VERSION 5.7 ;
  NOWIREEXTENSIONATPIN ON ;
  DIVIDERCHAR "/" ;
  BUSBITCHARS "[]" ;
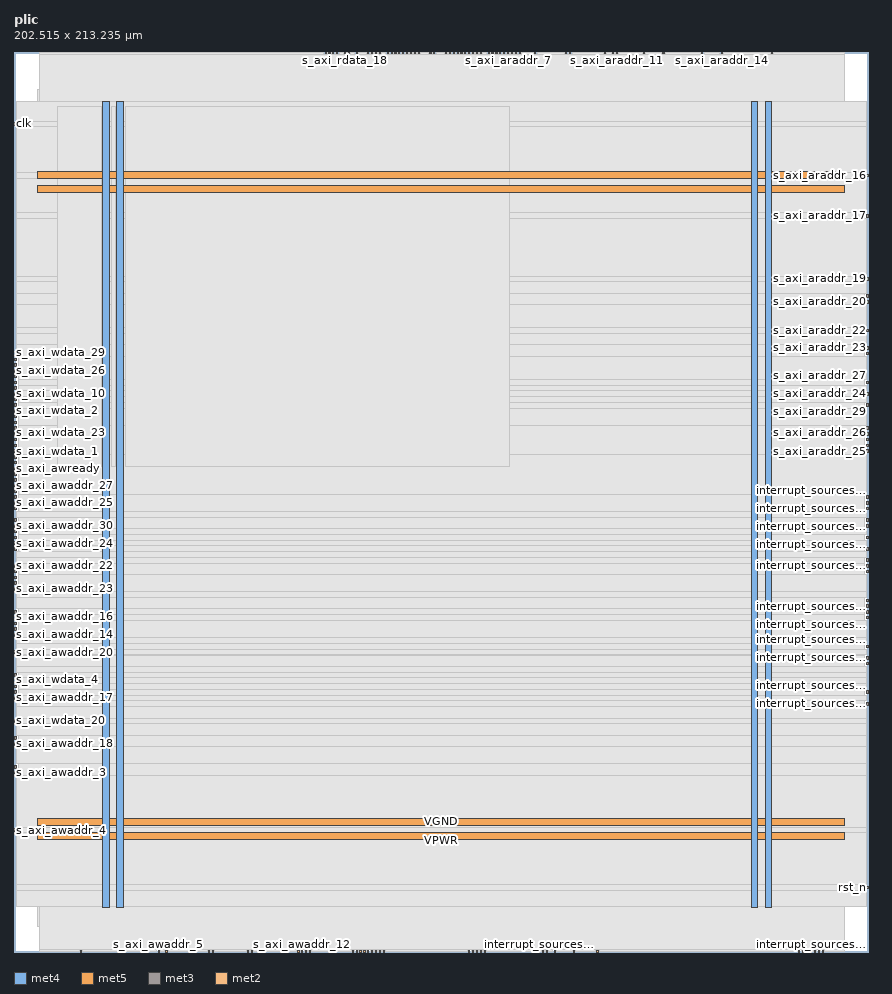
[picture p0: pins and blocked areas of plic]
MACRO plic
  CLASS BLOCK ;
  FOREIGN plic ;
  ORIGIN 0.000 0.000 ;
  SIZE 202.515 BY 213.235 ;
  PIN VGND
    DIRECTION INOUT ;
    USE GROUND ;
    PORT
      LAYER met4 ;
        RECT 24.340 10.640 25.940 201.520 ;
    END
    PORT
      LAYER met4 ;
        RECT 177.940 10.640 179.540 201.520 ;
    END
    PORT
      LAYER met5 ;
        RECT 5.520 30.030 196.880 31.630 ;
    END
    PORT
      LAYER met5 ;
        RECT 5.520 183.210 196.880 184.810 ;
    END
  END VGND
  PIN VPWR
    DIRECTION INOUT ;
    USE POWER ;
    PORT
      LAYER met4 ;
        RECT 21.040 10.640 22.640 201.520 ;
    END
    PORT
      LAYER met4 ;
        RECT 174.640 10.640 176.240 201.520 ;
    END
    PORT
      LAYER met5 ;
        RECT 5.520 26.730 196.880 28.330 ;
    END
    PORT
      LAYER met5 ;
        RECT 5.520 179.910 196.880 181.510 ;
    END
  END VPWR
  PIN clk
    DIRECTION INPUT ;
    USE SIGNAL ;
    ANTENNAGATEAREA 1.286700 ;
    ANTENNADIFFAREA 0.434700 ;
    PORT
      LAYER met3 ;
        RECT 0.000 195.880 0.600 196.480 ;
    END
  END clk
  PIN ext_irq
    DIRECTION OUTPUT ;
    USE SIGNAL ;
    ANTENNAGATEAREA 0.434700 ;
    ANTENNADIFFAREA 0.434700 ;
    PORT
      LAYER met2 ;
        RECT 111.410 0.000 111.690 0.280 ;
    END
  END ext_irq
  PIN interrupt_sources_0
    DIRECTION INPUT ;
    USE SIGNAL ;
    ANTENNAGATEAREA 0.647700 ;
    ANTENNADIFFAREA 0.434700 ;
    PORT
      LAYER met2 ;
        RECT 191.450 0.000 191.730 0.280 ;
    END
  END interrupt_sources_0
  PIN interrupt_sources_1
    DIRECTION INPUT ;
    USE SIGNAL ;
    ANTENNAGATEAREA 0.647700 ;
    ANTENNADIFFAREA 0.434700 ;
    PORT
      LAYER met3 ;
        RECT 201.915 104.760 202.515 105.360 ;
    END
  END interrupt_sources_1
  PIN interrupt_sources_10
    DIRECTION INPUT ;
    USE SIGNAL ;
    ANTENNAGATEAREA 0.647700 ;
    ANTENNADIFFAREA 0.434700 ;
    PORT
      LAYER met3 ;
        RECT 201.915 61.240 202.515 61.840 ;
    END
  END interrupt_sources_10
  PIN interrupt_sources_11
    DIRECTION INPUT ;
    USE SIGNAL ;
    ANTENNAGATEAREA 0.647700 ;
    ANTENNADIFFAREA 0.434700 ;
    PORT
      LAYER met3 ;
        RECT 201.915 69.400 202.515 70.000 ;
    END
  END interrupt_sources_11
  PIN interrupt_sources_12
    DIRECTION INPUT ;
    USE SIGNAL ;
    ANTENNAGATEAREA 0.647700 ;
    ANTENNADIFFAREA 0.434700 ;
    PORT
      LAYER met3 ;
        RECT 201.915 102.040 202.515 102.640 ;
    END
  END interrupt_sources_12
  PIN interrupt_sources_13
    DIRECTION INPUT ;
    USE SIGNAL ;
    ANTENNAGATEAREA 0.647700 ;
    ANTENNADIFFAREA 0.434700 ;
    PORT
      LAYER met3 ;
        RECT 201.915 58.520 202.515 59.120 ;
    END
  END interrupt_sources_13
  PIN interrupt_sources_14
    DIRECTION INPUT ;
    USE SIGNAL ;
    ANTENNAGATEAREA 0.647700 ;
    ANTENNADIFFAREA 0.434700 ;
    PORT
      LAYER met2 ;
        RECT 125.210 0.000 125.490 0.280 ;
    END
  END interrupt_sources_14
  PIN interrupt_sources_15
    DIRECTION INPUT ;
    USE SIGNAL ;
    ANTENNAGATEAREA 0.647700 ;
    ANTENNADIFFAREA 0.434700 ;
    PORT
      LAYER met3 ;
        RECT 201.915 81.640 202.515 82.240 ;
    END
  END interrupt_sources_15
  PIN interrupt_sources_16
    DIRECTION INPUT ;
    USE SIGNAL ;
    ANTENNAGATEAREA 0.647700 ;
    ANTENNADIFFAREA 0.434700 ;
    PORT
      LAYER met2 ;
        RECT 189.610 0.000 189.890 0.280 ;
    END
  END interrupt_sources_16
  PIN interrupt_sources_17
    DIRECTION INPUT ;
    USE SIGNAL ;
    ANTENNAGATEAREA 0.647700 ;
    ANTENNADIFFAREA 0.434700 ;
    PORT
      LAYER met3 ;
        RECT 201.915 107.480 202.515 108.080 ;
    END
  END interrupt_sources_17
  PIN interrupt_sources_18
    DIRECTION INPUT ;
    USE SIGNAL ;
    ANTENNAGATEAREA 0.647700 ;
    ANTENNADIFFAREA 0.434700 ;
    PORT
      LAYER met3 ;
        RECT 201.915 72.120 202.515 72.720 ;
    END
  END interrupt_sources_18
  PIN interrupt_sources_19
    DIRECTION INPUT ;
    USE SIGNAL ;
    ANTENNAGATEAREA 0.647700 ;
    ANTENNADIFFAREA 0.434700 ;
    PORT
      LAYER met2 ;
        RECT 187.770 0.000 188.050 0.280 ;
    END
  END interrupt_sources_19
  PIN interrupt_sources_2
    DIRECTION INPUT ;
    USE SIGNAL ;
    ANTENNAGATEAREA 0.647700 ;
    ANTENNADIFFAREA 0.434700 ;
    PORT
      LAYER met3 ;
        RECT 201.915 106.120 202.515 106.720 ;
    END
  END interrupt_sources_2
  PIN interrupt_sources_20
    DIRECTION INPUT ;
    USE SIGNAL ;
    ANTENNAGATEAREA 0.647700 ;
    ANTENNADIFFAREA 0.434700 ;
    PORT
      LAYER met2 ;
        RECT 138.090 0.000 138.370 0.280 ;
    END
  END interrupt_sources_20
  PIN interrupt_sources_21
    DIRECTION INPUT ;
    USE SIGNAL ;
    ANTENNAGATEAREA 0.647700 ;
    ANTENNADIFFAREA 0.434700 ;
    PORT
      LAYER met2 ;
        RECT 186.850 0.000 187.130 0.280 ;
    END
  END interrupt_sources_21
  PIN interrupt_sources_22
    DIRECTION INPUT ;
    USE SIGNAL ;
    ANTENNAGATEAREA 0.647700 ;
    ANTENNADIFFAREA 0.434700 ;
    PORT
      LAYER met2 ;
        RECT 127.970 0.000 128.250 0.280 ;
    END
  END interrupt_sources_22
  PIN interrupt_sources_23
    DIRECTION INPUT ;
    USE SIGNAL ;
    ANTENNAGATEAREA 0.647700 ;
    ANTENNADIFFAREA 0.434700 ;
    PORT
      LAYER met2 ;
        RECT 126.130 0.000 126.410 0.280 ;
    END
  END interrupt_sources_23
  PIN interrupt_sources_24
    DIRECTION INPUT ;
    USE SIGNAL ;
    ANTENNAGATEAREA 0.647700 ;
    ANTENNADIFFAREA 0.434700 ;
    PORT
      LAYER met3 ;
        RECT 201.915 83.000 202.515 83.600 ;
    END
  END interrupt_sources_24
  PIN interrupt_sources_25
    DIRECTION INPUT ;
    USE SIGNAL ;
    ANTENNAGATEAREA 0.647700 ;
    ANTENNADIFFAREA 0.434700 ;
    PORT
      LAYER met3 ;
        RECT 201.915 68.040 202.515 68.640 ;
    END
  END interrupt_sources_25
  PIN interrupt_sources_26
    DIRECTION INPUT ;
    USE SIGNAL ;
    ANTENNAGATEAREA 0.647700 ;
    ANTENNADIFFAREA 0.434700 ;
    PORT
      LAYER met3 ;
        RECT 201.915 91.160 202.515 91.760 ;
    END
  END interrupt_sources_26
  PIN interrupt_sources_27
    DIRECTION INPUT ;
    USE SIGNAL ;
    ANTENNAGATEAREA 0.647700 ;
    ANTENNADIFFAREA 0.434700 ;
    PORT
      LAYER met2 ;
        RECT 190.530 0.000 190.810 0.280 ;
    END
  END interrupt_sources_27
  PIN interrupt_sources_28
    DIRECTION INPUT ;
    USE SIGNAL ;
    ANTENNAGATEAREA 0.647700 ;
    ANTENNADIFFAREA 0.434700 ;
    PORT
      LAYER met3 ;
        RECT 201.915 97.960 202.515 98.560 ;
    END
  END interrupt_sources_28
  PIN interrupt_sources_29
    DIRECTION INPUT ;
    USE SIGNAL ;
    ANTENNAGATEAREA 0.647700 ;
    ANTENNADIFFAREA 0.434700 ;
    PORT
      LAYER met3 ;
        RECT 201.915 89.800 202.515 90.400 ;
    END
  END interrupt_sources_29
  PIN interrupt_sources_3
    DIRECTION INPUT ;
    USE SIGNAL ;
    ANTENNAGATEAREA 0.647700 ;
    ANTENNADIFFAREA 0.434700 ;
    PORT
      LAYER met2 ;
        RECT 185.930 0.000 186.210 0.280 ;
    END
  END interrupt_sources_3
  PIN interrupt_sources_30
    DIRECTION INPUT ;
    USE SIGNAL ;
    ANTENNAGATEAREA 0.647700 ;
    ANTENNADIFFAREA 0.434700 ;
    PORT
      LAYER met3 ;
        RECT 201.915 95.240 202.515 95.840 ;
    END
  END interrupt_sources_30
  PIN interrupt_sources_31
    DIRECTION INPUT ;
    USE SIGNAL ;
    ANTENNAGATEAREA 0.647700 ;
    ANTENNADIFFAREA 0.434700 ;
    PORT
      LAYER met3 ;
        RECT 201.915 92.520 202.515 93.120 ;
    END
  END interrupt_sources_31
  PIN interrupt_sources_4
    DIRECTION INPUT ;
    USE SIGNAL ;
    ANTENNAGATEAREA 0.647700 ;
    ANTENNADIFFAREA 0.434700 ;
    PORT
      LAYER met3 ;
        RECT 201.915 80.280 202.515 80.880 ;
    END
  END interrupt_sources_4
  PIN interrupt_sources_5
    DIRECTION INPUT ;
    USE SIGNAL ;
    ANTENNAGATEAREA 0.647700 ;
    ANTENNADIFFAREA 0.434700 ;
    PORT
      LAYER met2 ;
        RECT 188.690 0.000 188.970 0.280 ;
    END
  END interrupt_sources_5
  PIN interrupt_sources_6
    DIRECTION INPUT ;
    USE SIGNAL ;
    ANTENNAGATEAREA 0.647700 ;
    ANTENNADIFFAREA 0.434700 ;
    PORT
      LAYER met2 ;
        RECT 124.290 0.000 124.570 0.280 ;
    END
  END interrupt_sources_6
  PIN interrupt_sources_7
    DIRECTION INPUT ;
    USE SIGNAL ;
    ANTENNAGATEAREA 0.647700 ;
    ANTENNADIFFAREA 0.434700 ;
    PORT
      LAYER met2 ;
        RECT 132.570 0.000 132.850 0.280 ;
    END
  END interrupt_sources_7
  PIN interrupt_sources_8
    DIRECTION INPUT ;
    USE SIGNAL ;
    ANTENNAGATEAREA 0.647700 ;
    ANTENNADIFFAREA 0.434700 ;
    PORT
      LAYER met3 ;
        RECT 201.915 78.920 202.515 79.520 ;
    END
  END interrupt_sources_8
  PIN interrupt_sources_9
    DIRECTION INPUT ;
    USE SIGNAL ;
    ANTENNAGATEAREA 0.647700 ;
    ANTENNADIFFAREA 0.434700 ;
    PORT
      LAYER met3 ;
        RECT 201.915 100.680 202.515 101.280 ;
    END
  END interrupt_sources_9
  PIN rst_n
    DIRECTION INPUT ;
    USE SIGNAL ;
    ANTENNAGATEAREA 0.647700 ;
    ANTENNADIFFAREA 0.434700 ;
    PORT
      LAYER met3 ;
        RECT 201.915 15.000 202.515 15.600 ;
    END
  END rst_n
  PIN s_axi_araddr_0
    DIRECTION INPUT ;
    USE SIGNAL ;
    ANTENNAGATEAREA 0.647700 ;
    ANTENNADIFFAREA 0.434700 ;
    PORT
      LAYER met2 ;
        RECT 130.730 212.955 131.010 213.235 ;
    END
  END s_axi_araddr_0
  PIN s_axi_araddr_1
    DIRECTION INPUT ;
    USE SIGNAL ;
    ANTENNAGATEAREA 0.647700 ;
    ANTENNADIFFAREA 0.434700 ;
    PORT
      LAYER met2 ;
        RECT 116.010 212.955 116.290 213.235 ;
    END
  END s_axi_araddr_1
  PIN s_axi_araddr_10
    DIRECTION INPUT ;
    USE SIGNAL ;
    ANTENNAGATEAREA 0.647700 ;
    ANTENNADIFFAREA 0.434700 ;
    PORT
      LAYER met2 ;
        RECT 131.650 212.955 131.930 213.235 ;
    END
  END s_axi_araddr_10
  PIN s_axi_araddr_11
    DIRECTION INPUT ;
    USE SIGNAL ;
    ANTENNAGATEAREA 0.647700 ;
    ANTENNADIFFAREA 0.434700 ;
    PORT
      LAYER met2 ;
        RECT 142.690 212.955 142.970 213.235 ;
    END
  END s_axi_araddr_11
  PIN s_axi_araddr_12
    DIRECTION INPUT ;
    USE SIGNAL ;
    ANTENNAGATEAREA 0.647700 ;
    ANTENNADIFFAREA 0.434700 ;
    PORT
      LAYER met2 ;
        RECT 149.130 212.955 149.410 213.235 ;
    END
  END s_axi_araddr_12
  PIN s_axi_araddr_13
    DIRECTION INPUT ;
    USE SIGNAL ;
    ANTENNAGATEAREA 0.647700 ;
    ANTENNADIFFAREA 0.434700 ;
    PORT
      LAYER met2 ;
        RECT 153.730 212.955 154.010 213.235 ;
    END
  END s_axi_araddr_13
  PIN s_axi_araddr_14
    DIRECTION INPUT ;
    USE SIGNAL ;
    ANTENNAGATEAREA 0.647700 ;
    ANTENNADIFFAREA 0.434700 ;
    PORT
      LAYER met2 ;
        RECT 167.530 212.955 167.810 213.235 ;
    END
  END s_axi_araddr_14
  PIN s_axi_araddr_15
    DIRECTION INPUT ;
    USE SIGNAL ;
    ANTENNAGATEAREA 0.647700 ;
    ANTENNADIFFAREA 0.434700 ;
    PORT
      LAYER met2 ;
        RECT 179.490 212.955 179.770 213.235 ;
    END
  END s_axi_araddr_15
  PIN s_axi_araddr_16
    DIRECTION INPUT ;
    USE SIGNAL ;
    ANTENNAGATEAREA 0.647700 ;
    ANTENNADIFFAREA 0.434700 ;
    PORT
      LAYER met3 ;
        RECT 201.915 183.640 202.515 184.240 ;
    END
  END s_axi_araddr_16
  PIN s_axi_araddr_17
    DIRECTION INPUT ;
    USE SIGNAL ;
    ANTENNAGATEAREA 0.647700 ;
    ANTENNADIFFAREA 0.434700 ;
    PORT
      LAYER met3 ;
        RECT 201.915 174.120 202.515 174.720 ;
    END
  END s_axi_araddr_17
  PIN s_axi_araddr_18
    DIRECTION INPUT ;
    USE SIGNAL ;
    ANTENNAGATEAREA 0.647700 ;
    ANTENNADIFFAREA 0.434700 ;
    PORT
      LAYER met2 ;
        RECT 162.930 212.955 163.210 213.235 ;
    END
  END s_axi_araddr_18
  PIN s_axi_araddr_19
    DIRECTION INPUT ;
    USE SIGNAL ;
    ANTENNAGATEAREA 0.647700 ;
    ANTENNADIFFAREA 0.434700 ;
    PORT
      LAYER met3 ;
        RECT 201.915 159.160 202.515 159.760 ;
    END
  END s_axi_araddr_19
  PIN s_axi_araddr_2
    DIRECTION INPUT ;
    USE SIGNAL ;
    ANTENNAGATEAREA 0.647700 ;
    ANTENNADIFFAREA 0.434700 ;
    PORT
      LAYER met2 ;
        RECT 123.370 212.955 123.650 213.235 ;
    END
  END s_axi_araddr_2
  PIN s_axi_araddr_20
    DIRECTION INPUT ;
    USE SIGNAL ;
    ANTENNAGATEAREA 0.647700 ;
    ANTENNADIFFAREA 0.434700 ;
    PORT
      LAYER met3 ;
        RECT 201.915 153.720 202.515 154.320 ;
    END
  END s_axi_araddr_20
  PIN s_axi_araddr_21
    DIRECTION INPUT ;
    USE SIGNAL ;
    ANTENNAGATEAREA 0.647700 ;
    ANTENNADIFFAREA 0.434700 ;
    PORT
      LAYER met3 ;
        RECT 201.915 155.080 202.515 155.680 ;
    END
  END s_axi_araddr_21
  PIN s_axi_araddr_22
    DIRECTION INPUT ;
    USE SIGNAL ;
    ANTENNAGATEAREA 0.647700 ;
    ANTENNADIFFAREA 0.434700 ;
    PORT
      LAYER met3 ;
        RECT 201.915 146.920 202.515 147.520 ;
    END
  END s_axi_araddr_22
  PIN s_axi_araddr_23
    DIRECTION INPUT ;
    USE SIGNAL ;
    ANTENNAGATEAREA 0.647700 ;
    ANTENNADIFFAREA 0.434700 ;
    PORT
      LAYER met3 ;
        RECT 201.915 142.840 202.515 143.440 ;
    END
  END s_axi_araddr_23
  PIN s_axi_araddr_24
    DIRECTION INPUT ;
    USE SIGNAL ;
    ANTENNAGATEAREA 0.647700 ;
    ANTENNADIFFAREA 0.434700 ;
    PORT
      LAYER met3 ;
        RECT 201.915 131.960 202.515 132.560 ;
    END
  END s_axi_araddr_24
  PIN s_axi_araddr_25
    DIRECTION INPUT ;
    USE SIGNAL ;
    ANTENNAGATEAREA 0.647700 ;
    ANTENNADIFFAREA 0.434700 ;
    PORT
      LAYER met3 ;
        RECT 201.915 118.360 202.515 118.960 ;
    END
  END s_axi_araddr_25
  PIN s_axi_araddr_26
    DIRECTION INPUT ;
    USE SIGNAL ;
    ANTENNAGATEAREA 0.647700 ;
    ANTENNADIFFAREA 0.434700 ;
    PORT
      LAYER met3 ;
        RECT 201.915 121.080 202.515 121.680 ;
    END
  END s_axi_araddr_26
  PIN s_axi_araddr_27
    DIRECTION INPUT ;
    USE SIGNAL ;
    ANTENNAGATEAREA 0.647700 ;
    ANTENNADIFFAREA 0.434700 ;
    PORT
      LAYER met3 ;
        RECT 201.915 134.680 202.515 135.280 ;
    END
  END s_axi_araddr_27
  PIN s_axi_araddr_28
    DIRECTION INPUT ;
    USE SIGNAL ;
    ANTENNAGATEAREA 0.647700 ;
    ANTENNADIFFAREA 0.434700 ;
    PORT
      LAYER met3 ;
        RECT 201.915 141.480 202.515 142.080 ;
    END
  END s_axi_araddr_28
  PIN s_axi_araddr_29
    DIRECTION INPUT ;
    USE SIGNAL ;
    ANTENNAGATEAREA 0.647700 ;
    ANTENNADIFFAREA 0.434700 ;
    PORT
      LAYER met3 ;
        RECT 201.915 129.240 202.515 129.840 ;
    END
  END s_axi_araddr_29
  PIN s_axi_araddr_3
    DIRECTION INPUT ;
    USE SIGNAL ;
    ANTENNAGATEAREA 0.647700 ;
    ANTENNADIFFAREA 0.434700 ;
    PORT
      LAYER met2 ;
        RECT 117.850 212.955 118.130 213.235 ;
    END
  END s_axi_araddr_3
  PIN s_axi_araddr_30
    DIRECTION INPUT ;
    USE SIGNAL ;
    ANTENNAGATEAREA 0.647700 ;
    ANTENNADIFFAREA 0.434700 ;
    PORT
      LAYER met3 ;
        RECT 201.915 119.720 202.515 120.320 ;
    END
  END s_axi_araddr_30
  PIN s_axi_araddr_31
    DIRECTION INPUT ;
    USE SIGNAL ;
    ANTENNAGATEAREA 0.647700 ;
    ANTENNADIFFAREA 0.434700 ;
    PORT
      LAYER met3 ;
        RECT 201.915 122.440 202.515 123.040 ;
    END
  END s_axi_araddr_31
  PIN s_axi_araddr_4
    DIRECTION INPUT ;
    USE SIGNAL ;
    ANTENNAGATEAREA 0.647700 ;
    ANTENNADIFFAREA 0.434700 ;
    PORT
      LAYER met3 ;
        RECT 201.915 123.800 202.515 124.400 ;
    END
  END s_axi_araddr_4
  PIN s_axi_araddr_5
    DIRECTION INPUT ;
    USE SIGNAL ;
    ANTENNAGATEAREA 0.647700 ;
    ANTENNADIFFAREA 0.434700 ;
    PORT
      LAYER met2 ;
        RECT 141.770 212.955 142.050 213.235 ;
    END
  END s_axi_araddr_5
  PIN s_axi_araddr_6
    DIRECTION INPUT ;
    USE SIGNAL ;
    ANTENNAGATEAREA 0.647700 ;
    ANTENNADIFFAREA 0.434700 ;
    PORT
      LAYER met2 ;
        RECT 139.930 212.955 140.210 213.235 ;
    END
  END s_axi_araddr_6
  PIN s_axi_araddr_7
    DIRECTION INPUT ;
    USE SIGNAL ;
    ANTENNAGATEAREA 0.647700 ;
    ANTENNADIFFAREA 0.434700 ;
    PORT
      LAYER met2 ;
        RECT 116.930 212.955 117.210 213.235 ;
    END
  END s_axi_araddr_7
  PIN s_axi_araddr_8
    DIRECTION INPUT ;
    USE SIGNAL ;
    ANTENNAGATEAREA 0.647700 ;
    ANTENNADIFFAREA 0.434700 ;
    PORT
      LAYER met2 ;
        RECT 119.690 212.955 119.970 213.235 ;
    END
  END s_axi_araddr_8
  PIN s_axi_araddr_9
    DIRECTION INPUT ;
    USE SIGNAL ;
    ANTENNAGATEAREA 0.647700 ;
    ANTENNADIFFAREA 0.434700 ;
    PORT
      LAYER met2 ;
        RECT 118.770 212.955 119.050 213.235 ;
    END
  END s_axi_araddr_9
  PIN s_axi_arready
    DIRECTION OUTPUT ;
    USE SIGNAL ;
    ANTENNAGATEAREA 0.434700 ;
    ANTENNADIFFAREA 1.137600 ;
    PORT
      LAYER met2 ;
        RECT 115.090 212.955 115.370 213.235 ;
    END
  END s_axi_arready
  PIN s_axi_arvalid
    DIRECTION INPUT ;
    USE SIGNAL ;
    ANTENNAGATEAREA 0.647700 ;
    ANTENNADIFFAREA 0.434700 ;
    PORT
      LAYER met2 ;
        RECT 112.330 212.955 112.610 213.235 ;
    END
  END s_axi_arvalid
  PIN s_axi_awaddr_0
    DIRECTION INPUT ;
    USE SIGNAL ;
    ANTENNAGATEAREA 0.647700 ;
    ANTENNADIFFAREA 0.434700 ;
    PORT
      LAYER met2 ;
        RECT 35.970 0.000 36.250 0.280 ;
    END
  END s_axi_awaddr_0
  PIN s_axi_awaddr_1
    DIRECTION INPUT ;
    USE SIGNAL ;
    ANTENNAGATEAREA 0.647700 ;
    ANTENNADIFFAREA 0.434700 ;
    PORT
      LAYER met2 ;
        RECT 25.850 0.000 26.130 0.280 ;
    END
  END s_axi_awaddr_1
  PIN s_axi_awaddr_10
    DIRECTION INPUT ;
    USE SIGNAL ;
    ANTENNAGATEAREA 0.647700 ;
    ANTENNADIFFAREA 0.434700 ;
    PORT
      LAYER met2 ;
        RECT 56.210 0.000 56.490 0.280 ;
    END
  END s_axi_awaddr_10
  PIN s_axi_awaddr_11
    DIRECTION INPUT ;
    USE SIGNAL ;
    ANTENNAGATEAREA 0.647700 ;
    ANTENNADIFFAREA 0.434700 ;
    PORT
      LAYER met2 ;
        RECT 47.010 0.000 47.290 0.280 ;
    END
  END s_axi_awaddr_11
  PIN s_axi_awaddr_12
    DIRECTION INPUT ;
    USE SIGNAL ;
    ANTENNAGATEAREA 0.647700 ;
    ANTENNADIFFAREA 0.434700 ;
    PORT
      LAYER met2 ;
        RECT 68.170 0.000 68.450 0.280 ;
    END
  END s_axi_awaddr_12
  PIN s_axi_awaddr_13
    DIRECTION INPUT ;
    USE SIGNAL ;
    ANTENNAGATEAREA 0.647700 ;
    ANTENNADIFFAREA 0.434700 ;
    PORT
      LAYER met2 ;
        RECT 67.250 0.000 67.530 0.280 ;
    END
  END s_axi_awaddr_13
  PIN s_axi_awaddr_14
    DIRECTION INPUT ;
    USE SIGNAL ;
    ANTENNAGATEAREA 0.647700 ;
    ANTENNADIFFAREA 0.434700 ;
    PORT
      LAYER met3 ;
        RECT 0.000 74.840 0.600 75.440 ;
    END
  END s_axi_awaddr_14
  PIN s_axi_awaddr_15
    DIRECTION INPUT ;
    USE SIGNAL ;
    ANTENNAGATEAREA 0.647700 ;
    ANTENNADIFFAREA 0.434700 ;
    PORT
      LAYER met3 ;
        RECT 0.000 65.320 0.600 65.920 ;
    END
  END s_axi_awaddr_15
  PIN s_axi_awaddr_16
    DIRECTION INPUT ;
    USE SIGNAL ;
    ANTENNAGATEAREA 0.647700 ;
    ANTENNADIFFAREA 0.434700 ;
    PORT
      LAYER met3 ;
        RECT 0.000 77.560 0.600 78.160 ;
    END
  END s_axi_awaddr_16
  PIN s_axi_awaddr_17
    DIRECTION INPUT ;
    USE SIGNAL ;
    ANTENNAGATEAREA 0.647700 ;
    ANTENNADIFFAREA 0.434700 ;
    PORT
      LAYER met3 ;
        RECT 0.000 59.880 0.600 60.480 ;
    END
  END s_axi_awaddr_17
  PIN s_axi_awaddr_18
    DIRECTION INPUT ;
    USE SIGNAL ;
    ANTENNAGATEAREA 0.647700 ;
    ANTENNADIFFAREA 0.434700 ;
    PORT
      LAYER met3 ;
        RECT 0.000 49.000 0.600 49.600 ;
    END
  END s_axi_awaddr_18
  PIN s_axi_awaddr_19
    DIRECTION INPUT ;
    USE SIGNAL ;
    ANTENNAGATEAREA 0.647700 ;
    ANTENNADIFFAREA 0.434700 ;
    PORT
      LAYER met3 ;
        RECT 0.000 61.240 0.600 61.840 ;
    END
  END s_axi_awaddr_19
  PIN s_axi_awaddr_2
    DIRECTION INPUT ;
    USE SIGNAL ;
    ANTENNAGATEAREA 0.647700 ;
    ANTENNADIFFAREA 0.434700 ;
    PORT
      LAYER met2 ;
        RECT 15.730 0.000 16.010 0.280 ;
    END
  END s_axi_awaddr_2
  PIN s_axi_awaddr_20
    DIRECTION INPUT ;
    USE SIGNAL ;
    ANTENNAGATEAREA 0.647700 ;
    ANTENNADIFFAREA 0.434700 ;
    PORT
      LAYER met3 ;
        RECT 0.000 70.760 0.600 71.360 ;
    END
  END s_axi_awaddr_20
  PIN s_axi_awaddr_21
    DIRECTION INPUT ;
    USE SIGNAL ;
    ANTENNAGATEAREA 0.647700 ;
    ANTENNADIFFAREA 0.434700 ;
    PORT
      LAYER met3 ;
        RECT 0.000 76.200 0.600 76.800 ;
    END
  END s_axi_awaddr_21
  PIN s_axi_awaddr_22
    DIRECTION INPUT ;
    USE SIGNAL ;
    ANTENNAGATEAREA 0.647700 ;
    ANTENNADIFFAREA 0.434700 ;
    PORT
      LAYER met3 ;
        RECT 0.000 91.160 0.600 91.760 ;
    END
  END s_axi_awaddr_22
  PIN s_axi_awaddr_23
    DIRECTION INPUT ;
    USE SIGNAL ;
    ANTENNAGATEAREA 0.647700 ;
    ANTENNADIFFAREA 0.434700 ;
    PORT
      LAYER met3 ;
        RECT 0.000 85.720 0.600 86.320 ;
    END
  END s_axi_awaddr_23
  PIN s_axi_awaddr_24
    DIRECTION INPUT ;
    USE SIGNAL ;
    ANTENNAGATEAREA 0.647700 ;
    ANTENNADIFFAREA 0.434700 ;
    PORT
      LAYER met3 ;
        RECT 0.000 96.600 0.600 97.200 ;
    END
  END s_axi_awaddr_24
  PIN s_axi_awaddr_25
    DIRECTION INPUT ;
    USE SIGNAL ;
    ANTENNAGATEAREA 0.647700 ;
    ANTENNADIFFAREA 0.434700 ;
    PORT
      LAYER met3 ;
        RECT 0.000 106.120 0.600 106.720 ;
    END
  END s_axi_awaddr_25
  PIN s_axi_awaddr_26
    DIRECTION INPUT ;
    USE SIGNAL ;
    ANTENNAGATEAREA 0.647700 ;
    ANTENNADIFFAREA 0.434700 ;
    PORT
      LAYER met3 ;
        RECT 0.000 104.760 0.600 105.360 ;
    END
  END s_axi_awaddr_26
  PIN s_axi_awaddr_27
    DIRECTION INPUT ;
    USE SIGNAL ;
    ANTENNAGATEAREA 0.647700 ;
    ANTENNADIFFAREA 0.434700 ;
    PORT
      LAYER met3 ;
        RECT 0.000 110.200 0.600 110.800 ;
    END
  END s_axi_awaddr_27
  PIN s_axi_awaddr_28
    DIRECTION INPUT ;
    USE SIGNAL ;
    ANTENNAGATEAREA 0.647700 ;
    ANTENNADIFFAREA 0.434700 ;
    PORT
      LAYER met3 ;
        RECT 0.000 99.320 0.600 99.920 ;
    END
  END s_axi_awaddr_28
  PIN s_axi_awaddr_29
    DIRECTION INPUT ;
    USE SIGNAL ;
    ANTENNAGATEAREA 0.647700 ;
    ANTENNADIFFAREA 0.434700 ;
    PORT
      LAYER met3 ;
        RECT 0.000 87.080 0.600 87.680 ;
    END
  END s_axi_awaddr_29
  PIN s_axi_awaddr_3
    DIRECTION INPUT ;
    USE SIGNAL ;
    ANTENNAGATEAREA 0.647700 ;
    ANTENNADIFFAREA 0.434700 ;
    PORT
      LAYER met3 ;
        RECT 0.000 42.200 0.600 42.800 ;
    END
  END s_axi_awaddr_3
  PIN s_axi_awaddr_30
    DIRECTION INPUT ;
    USE SIGNAL ;
    ANTENNAGATEAREA 0.647700 ;
    ANTENNADIFFAREA 0.434700 ;
    PORT
      LAYER met3 ;
        RECT 0.000 100.680 0.600 101.280 ;
    END
  END s_axi_awaddr_30
  PIN s_axi_awaddr_31
    DIRECTION INPUT ;
    USE SIGNAL ;
    ANTENNAGATEAREA 0.647700 ;
    ANTENNADIFFAREA 0.434700 ;
    PORT
      LAYER met3 ;
        RECT 0.000 88.440 0.600 89.040 ;
    END
  END s_axi_awaddr_31
  PIN s_axi_awaddr_4
    DIRECTION INPUT ;
    USE SIGNAL ;
    ANTENNAGATEAREA 0.647700 ;
    ANTENNADIFFAREA 0.434700 ;
    PORT
      LAYER met3 ;
        RECT 0.000 28.600 0.600 29.200 ;
    END
  END s_axi_awaddr_4
  PIN s_axi_awaddr_5
    DIRECTION INPUT ;
    USE SIGNAL ;
    ANTENNAGATEAREA 0.647700 ;
    ANTENNADIFFAREA 0.434700 ;
    PORT
      LAYER met2 ;
        RECT 34.130 0.000 34.410 0.280 ;
    END
  END s_axi_awaddr_5
  PIN s_axi_awaddr_6
    DIRECTION INPUT ;
    USE SIGNAL ;
    ANTENNAGATEAREA 0.647700 ;
    ANTENNADIFFAREA 0.434700 ;
    PORT
      LAYER met2 ;
        RECT 46.090 0.000 46.370 0.280 ;
    END
  END s_axi_awaddr_6
  PIN s_axi_awaddr_7
    DIRECTION INPUT ;
    USE SIGNAL ;
    ANTENNAGATEAREA 0.647700 ;
    ANTENNADIFFAREA 0.434700 ;
    PORT
      LAYER met2 ;
        RECT 55.290 0.000 55.570 0.280 ;
    END
  END s_axi_awaddr_7
  PIN s_axi_awaddr_8
    DIRECTION INPUT ;
    USE SIGNAL ;
    ANTENNAGATEAREA 0.647700 ;
    ANTENNADIFFAREA 0.434700 ;
    PORT
      LAYER met2 ;
        RECT 70.010 0.000 70.290 0.280 ;
    END
  END s_axi_awaddr_8
  PIN s_axi_awaddr_9
    DIRECTION INPUT ;
    USE SIGNAL ;
    ANTENNAGATEAREA 0.647700 ;
    ANTENNADIFFAREA 0.434700 ;
    PORT
      LAYER met2 ;
        RECT 69.090 0.000 69.370 0.280 ;
    END
  END s_axi_awaddr_9
  PIN s_axi_awready
    DIRECTION OUTPUT ;
    USE SIGNAL ;
    ANTENNAGATEAREA 0.434700 ;
    ANTENNADIFFAREA 1.137600 ;
    PORT
      LAYER met3 ;
        RECT 0.000 114.280 0.600 114.880 ;
    END
  END s_axi_awready
  PIN s_axi_awvalid
    DIRECTION INPUT ;
    USE SIGNAL ;
    ANTENNAGATEAREA 0.647700 ;
    ANTENNADIFFAREA 0.434700 ;
    PORT
      LAYER met3 ;
        RECT 0.000 112.920 0.600 113.520 ;
    END
  END s_axi_awvalid
  PIN s_axi_bready
    DIRECTION INPUT ;
    USE SIGNAL ;
    ANTENNAGATEAREA 0.647700 ;
    ANTENNADIFFAREA 0.434700 ;
    PORT
      LAYER met3 ;
        RECT 0.000 108.840 0.600 109.440 ;
    END
  END s_axi_bready
  PIN s_axi_bresp_0
    DIRECTION OUTPUT ;
    USE SIGNAL ;
    ANTENNAGATEAREA 0.434700 ;
    ANTENNADIFFAREA 0.775300 ;
    PORT
      LAYER met2 ;
        RECT 110.490 0.000 110.770 0.280 ;
    END
  END s_axi_bresp_0
  PIN s_axi_bresp_1
    DIRECTION OUTPUT ;
    USE SIGNAL ;
    ANTENNAGATEAREA 0.434700 ;
    ANTENNADIFFAREA 0.775300 ;
    PORT
      LAYER met2 ;
        RECT 107.730 0.000 108.010 0.280 ;
    END
  END s_axi_bresp_1
  PIN s_axi_bvalid
    DIRECTION OUTPUT ;
    USE SIGNAL ;
    ANTENNAGATEAREA 0.434700 ;
    ANTENNADIFFAREA 1.137600 ;
    PORT
      LAYER met3 ;
        RECT 0.000 111.560 0.600 112.160 ;
    END
  END s_axi_bvalid
  PIN s_axi_rdata_0
    DIRECTION OUTPUT ;
    USE SIGNAL ;
    ANTENNAGATEAREA 0.434700 ;
    ANTENNADIFFAREA 1.137600 ;
    PORT
      LAYER met2 ;
        RECT 114.170 212.955 114.450 213.235 ;
    END
  END s_axi_rdata_0
  PIN s_axi_rdata_1
    DIRECTION OUTPUT ;
    USE SIGNAL ;
    ANTENNAGATEAREA 0.434700 ;
    ANTENNADIFFAREA 1.137600 ;
    PORT
      LAYER met2 ;
        RECT 104.970 212.955 105.250 213.235 ;
    END
  END s_axi_rdata_1
  PIN s_axi_rdata_10
    DIRECTION OUTPUT ;
    USE SIGNAL ;
    ANTENNAGATEAREA 0.434700 ;
    ANTENNADIFFAREA 1.137600 ;
    PORT
      LAYER met2 ;
        RECT 86.570 212.955 86.850 213.235 ;
    END
  END s_axi_rdata_10
  PIN s_axi_rdata_11
    DIRECTION OUTPUT ;
    USE SIGNAL ;
    ANTENNAGATEAREA 0.434700 ;
    ANTENNADIFFAREA 1.137600 ;
    PORT
      LAYER met2 ;
        RECT 75.530 212.955 75.810 213.235 ;
    END
  END s_axi_rdata_11
  PIN s_axi_rdata_12
    DIRECTION OUTPUT ;
    USE SIGNAL ;
    ANTENNAGATEAREA 0.434700 ;
    ANTENNADIFFAREA 1.137600 ;
    PORT
      LAYER met2 ;
        RECT 79.210 212.955 79.490 213.235 ;
    END
  END s_axi_rdata_12
  PIN s_axi_rdata_13
    DIRECTION OUTPUT ;
    USE SIGNAL ;
    ANTENNAGATEAREA 0.434700 ;
    ANTENNADIFFAREA 1.137600 ;
    PORT
      LAYER met2 ;
        RECT 99.450 212.955 99.730 213.235 ;
    END
  END s_axi_rdata_13
  PIN s_axi_rdata_14
    DIRECTION OUTPUT ;
    USE SIGNAL ;
    ANTENNAGATEAREA 0.434700 ;
    ANTENNADIFFAREA 1.137600 ;
    PORT
      LAYER met2 ;
        RECT 113.250 212.955 113.530 213.235 ;
    END
  END s_axi_rdata_14
  PIN s_axi_rdata_15
    DIRECTION OUTPUT ;
    USE SIGNAL ;
    ANTENNAGATEAREA 0.434700 ;
    ANTENNADIFFAREA 1.137600 ;
    PORT
      LAYER met2 ;
        RECT 104.050 212.955 104.330 213.235 ;
    END
  END s_axi_rdata_15
  PIN s_axi_rdata_16
    DIRECTION OUTPUT ;
    USE SIGNAL ;
    ANTENNAGATEAREA 0.434700 ;
    ANTENNADIFFAREA 1.137600 ;
    PORT
      LAYER met2 ;
        RECT 108.650 212.955 108.930 213.235 ;
    END
  END s_axi_rdata_16
  PIN s_axi_rdata_17
    DIRECTION OUTPUT ;
    USE SIGNAL ;
    ANTENNAGATEAREA 0.434700 ;
    ANTENNADIFFAREA 1.137600 ;
    PORT
      LAYER met2 ;
        RECT 89.330 212.955 89.610 213.235 ;
    END
  END s_axi_rdata_17
  PIN s_axi_rdata_18
    DIRECTION OUTPUT ;
    USE SIGNAL ;
    ANTENNAGATEAREA 0.434700 ;
    ANTENNADIFFAREA 1.137600 ;
    PORT
      LAYER met2 ;
        RECT 78.290 212.955 78.570 213.235 ;
    END
  END s_axi_rdata_18
  PIN s_axi_rdata_19
    DIRECTION OUTPUT ;
    USE SIGNAL ;
    ANTENNAGATEAREA 0.434700 ;
    ANTENNADIFFAREA 1.137600 ;
    PORT
      LAYER met2 ;
        RECT 103.130 212.955 103.410 213.235 ;
    END
  END s_axi_rdata_19
  PIN s_axi_rdata_2
    DIRECTION OUTPUT ;
    USE SIGNAL ;
    ANTENNAGATEAREA 0.434700 ;
    ANTENNADIFFAREA 1.137600 ;
    PORT
      LAYER met2 ;
        RECT 95.770 212.955 96.050 213.235 ;
    END
  END s_axi_rdata_2
  PIN s_axi_rdata_20
    DIRECTION OUTPUT ;
    USE SIGNAL ;
    ANTENNAGATEAREA 0.434700 ;
    ANTENNADIFFAREA 1.137600 ;
    PORT
      LAYER met2 ;
        RECT 88.410 212.955 88.690 213.235 ;
    END
  END s_axi_rdata_20
  PIN s_axi_rdata_21
    DIRECTION OUTPUT ;
    USE SIGNAL ;
    ANTENNAGATEAREA 0.434700 ;
    ANTENNADIFFAREA 1.137600 ;
    PORT
      LAYER met2 ;
        RECT 93.010 212.955 93.290 213.235 ;
    END
  END s_axi_rdata_21
  PIN s_axi_rdata_22
    DIRECTION OUTPUT ;
    USE SIGNAL ;
    ANTENNAGATEAREA 0.434700 ;
    ANTENNADIFFAREA 1.137600 ;
    PORT
      LAYER met2 ;
        RECT 110.490 212.955 110.770 213.235 ;
    END
  END s_axi_rdata_22
  PIN s_axi_rdata_23
    DIRECTION OUTPUT ;
    USE SIGNAL ;
    ANTENNAGATEAREA 0.434700 ;
    ANTENNADIFFAREA 1.137600 ;
    PORT
      LAYER met2 ;
        RECT 93.930 212.955 94.210 213.235 ;
    END
  END s_axi_rdata_23
  PIN s_axi_rdata_24
    DIRECTION OUTPUT ;
    USE SIGNAL ;
    ANTENNAGATEAREA 0.434700 ;
    ANTENNADIFFAREA 1.137600 ;
    PORT
      LAYER met2 ;
        RECT 109.570 212.955 109.850 213.235 ;
    END
  END s_axi_rdata_24
  PIN s_axi_rdata_25
    DIRECTION OUTPUT ;
    USE SIGNAL ;
    ANTENNAGATEAREA 0.434700 ;
    ANTENNADIFFAREA 1.137600 ;
    PORT
      LAYER met2 ;
        RECT 74.610 212.955 74.890 213.235 ;
    END
  END s_axi_rdata_25
  PIN s_axi_rdata_26
    DIRECTION OUTPUT ;
    USE SIGNAL ;
    ANTENNAGATEAREA 0.434700 ;
    ANTENNADIFFAREA 1.137600 ;
    PORT
      LAYER met2 ;
        RECT 85.650 212.955 85.930 213.235 ;
    END
  END s_axi_rdata_26
  PIN s_axi_rdata_27
    DIRECTION OUTPUT ;
    USE SIGNAL ;
    ANTENNAGATEAREA 0.434700 ;
    ANTENNADIFFAREA 1.137600 ;
    PORT
      LAYER met2 ;
        RECT 81.050 212.955 81.330 213.235 ;
    END
  END s_axi_rdata_27
  PIN s_axi_rdata_28
    DIRECTION OUTPUT ;
    USE SIGNAL ;
    ANTENNAGATEAREA 0.434700 ;
    ANTENNADIFFAREA 1.137600 ;
    PORT
      LAYER met2 ;
        RECT 83.810 212.955 84.090 213.235 ;
    END
  END s_axi_rdata_28
  PIN s_axi_rdata_29
    DIRECTION OUTPUT ;
    USE SIGNAL ;
    ANTENNAGATEAREA 0.434700 ;
    ANTENNADIFFAREA 1.137600 ;
    PORT
      LAYER met2 ;
        RECT 84.730 212.955 85.010 213.235 ;
    END
  END s_axi_rdata_29
  PIN s_axi_rdata_3
    DIRECTION OUTPUT ;
    USE SIGNAL ;
    ANTENNAGATEAREA 0.434700 ;
    ANTENNADIFFAREA 1.137600 ;
    PORT
      LAYER met2 ;
        RECT 107.730 212.955 108.010 213.235 ;
    END
  END s_axi_rdata_3
  PIN s_axi_rdata_30
    DIRECTION OUTPUT ;
    USE SIGNAL ;
    ANTENNAGATEAREA 0.434700 ;
    ANTENNADIFFAREA 1.137600 ;
    PORT
      LAYER met2 ;
        RECT 102.210 212.955 102.490 213.235 ;
    END
  END s_axi_rdata_30
  PIN s_axi_rdata_31
    DIRECTION OUTPUT ;
    USE SIGNAL ;
    ANTENNAGATEAREA 0.434700 ;
    ANTENNADIFFAREA 1.137600 ;
    PORT
      LAYER met2 ;
        RECT 73.690 212.955 73.970 213.235 ;
    END
  END s_axi_rdata_31
  PIN s_axi_rdata_4
    DIRECTION OUTPUT ;
    USE SIGNAL ;
    ANTENNAGATEAREA 0.434700 ;
    ANTENNADIFFAREA 1.137600 ;
    PORT
      LAYER met2 ;
        RECT 76.450 212.955 76.730 213.235 ;
    END
  END s_axi_rdata_4
  PIN s_axi_rdata_5
    DIRECTION OUTPUT ;
    USE SIGNAL ;
    ANTENNAGATEAREA 0.434700 ;
    ANTENNADIFFAREA 1.137600 ;
    PORT
      LAYER met2 ;
        RECT 92.090 212.955 92.370 213.235 ;
    END
  END s_axi_rdata_5
  PIN s_axi_rdata_6
    DIRECTION OUTPUT ;
    USE SIGNAL ;
    ANTENNAGATEAREA 0.434700 ;
    ANTENNADIFFAREA 1.137600 ;
    PORT
      LAYER met2 ;
        RECT 91.170 212.955 91.450 213.235 ;
    END
  END s_axi_rdata_6
  PIN s_axi_rdata_7
    DIRECTION OUTPUT ;
    USE SIGNAL ;
    ANTENNAGATEAREA 0.434700 ;
    ANTENNADIFFAREA 1.137600 ;
    PORT
      LAYER met2 ;
        RECT 90.250 212.955 90.530 213.235 ;
    END
  END s_axi_rdata_7
  PIN s_axi_rdata_8
    DIRECTION OUTPUT ;
    USE SIGNAL ;
    ANTENNAGATEAREA 0.434700 ;
    ANTENNADIFFAREA 1.137600 ;
    PORT
      LAYER met2 ;
        RECT 98.530 212.955 98.810 213.235 ;
    END
  END s_axi_rdata_8
  PIN s_axi_rdata_9
    DIRECTION OUTPUT ;
    USE SIGNAL ;
    ANTENNAGATEAREA 0.434700 ;
    ANTENNADIFFAREA 1.137600 ;
    PORT
      LAYER met2 ;
        RECT 94.850 212.955 95.130 213.235 ;
    END
  END s_axi_rdata_9
  PIN s_axi_rready
    DIRECTION INPUT ;
    USE SIGNAL ;
    ANTENNAGATEAREA 0.647700 ;
    ANTENNADIFFAREA 0.434700 ;
    PORT
      LAYER met2 ;
        RECT 105.890 212.955 106.170 213.235 ;
    END
  END s_axi_rready
  PIN s_axi_rresp_0
    DIRECTION OUTPUT ;
    USE SIGNAL ;
    ANTENNAGATEAREA 0.434700 ;
    ANTENNADIFFAREA 0.775300 ;
    PORT
      LAYER met2 ;
        RECT 109.570 0.000 109.850 0.280 ;
    END
  END s_axi_rresp_0
  PIN s_axi_rresp_1
    DIRECTION OUTPUT ;
    USE SIGNAL ;
    ANTENNAGATEAREA 0.434700 ;
    ANTENNADIFFAREA 0.775300 ;
    PORT
      LAYER met2 ;
        RECT 108.650 0.000 108.930 0.280 ;
    END
  END s_axi_rresp_1
  PIN s_axi_rvalid
    DIRECTION OUTPUT ;
    USE SIGNAL ;
    ANTENNAGATEAREA 0.434700 ;
    ANTENNADIFFAREA 1.137600 ;
    PORT
      LAYER met2 ;
        RECT 106.810 212.955 107.090 213.235 ;
    END
  END s_axi_rvalid
  PIN s_axi_wdata_0
    DIRECTION INPUT ;
    USE SIGNAL ;
    ANTENNAGATEAREA 0.647700 ;
    ANTENNADIFFAREA 0.434700 ;
    PORT
      LAYER met3 ;
        RECT 0.000 95.240 0.600 95.840 ;
    END
  END s_axi_wdata_0
  PIN s_axi_wdata_1
    DIRECTION INPUT ;
    USE SIGNAL ;
    ANTENNAGATEAREA 0.647700 ;
    ANTENNADIFFAREA 0.434700 ;
    PORT
      LAYER met3 ;
        RECT 0.000 118.360 0.600 118.960 ;
    END
  END s_axi_wdata_1
  PIN s_axi_wdata_10
    DIRECTION INPUT ;
    USE SIGNAL ;
    ANTENNAGATEAREA 0.647700 ;
    ANTENNADIFFAREA 0.434700 ;
    PORT
      LAYER met3 ;
        RECT 0.000 131.960 0.600 132.560 ;
    END
  END s_axi_wdata_10
  PIN s_axi_wdata_11
    DIRECTION INPUT ;
    USE SIGNAL ;
    ANTENNAGATEAREA 0.647700 ;
    ANTENNADIFFAREA 0.434700 ;
    PORT
      LAYER met3 ;
        RECT 0.000 107.480 0.600 108.080 ;
    END
  END s_axi_wdata_11
  PIN s_axi_wdata_12
    DIRECTION INPUT ;
    USE SIGNAL ;
    ANTENNAGATEAREA 0.647700 ;
    ANTENNADIFFAREA 0.434700 ;
    PORT
      LAYER met3 ;
        RECT 0.000 115.640 0.600 116.240 ;
    END
  END s_axi_wdata_12
  PIN s_axi_wdata_13
    DIRECTION INPUT ;
    USE SIGNAL ;
    ANTENNAGATEAREA 0.647700 ;
    ANTENNADIFFAREA 0.434700 ;
    PORT
      LAYER met3 ;
        RECT 0.000 117.000 0.600 117.600 ;
    END
  END s_axi_wdata_13
  PIN s_axi_wdata_14
    DIRECTION INPUT ;
    USE SIGNAL ;
    ANTENNAGATEAREA 0.647700 ;
    ANTENNADIFFAREA 0.434700 ;
    PORT
      LAYER met3 ;
        RECT 0.000 102.040 0.600 102.640 ;
    END
  END s_axi_wdata_14
  PIN s_axi_wdata_15
    DIRECTION INPUT ;
    USE SIGNAL ;
    ANTENNAGATEAREA 0.647700 ;
    ANTENNADIFFAREA 0.434700 ;
    PORT
      LAYER met3 ;
        RECT 0.000 138.760 0.600 139.360 ;
    END
  END s_axi_wdata_15
  PIN s_axi_wdata_16
    DIRECTION INPUT ;
    USE SIGNAL ;
    ANTENNAGATEAREA 0.647700 ;
    ANTENNADIFFAREA 0.434700 ;
    PORT
      LAYER met2 ;
        RECT 83.810 0.000 84.090 0.280 ;
    END
  END s_axi_wdata_16
  PIN s_axi_wdata_17
    DIRECTION INPUT ;
    USE SIGNAL ;
    ANTENNAGATEAREA 0.647700 ;
    ANTENNADIFFAREA 0.434700 ;
    PORT
      LAYER met2 ;
        RECT 80.130 0.000 80.410 0.280 ;
    END
  END s_axi_wdata_17
  PIN s_axi_wdata_18
    DIRECTION INPUT ;
    USE SIGNAL ;
    ANTENNAGATEAREA 0.647700 ;
    ANTENNADIFFAREA 0.434700 ;
    PORT
      LAYER met3 ;
        RECT 0.000 119.720 0.600 120.320 ;
    END
  END s_axi_wdata_18
  PIN s_axi_wdata_19
    DIRECTION INPUT ;
    USE SIGNAL ;
    ANTENNAGATEAREA 0.647700 ;
    ANTENNADIFFAREA 0.434700 ;
    PORT
      LAYER met3 ;
        RECT 0.000 50.360 0.600 50.960 ;
    END
  END s_axi_wdata_19
  PIN s_axi_wdata_2
    DIRECTION INPUT ;
    USE SIGNAL ;
    ANTENNAGATEAREA 0.647700 ;
    ANTENNADIFFAREA 0.434700 ;
    PORT
      LAYER met3 ;
        RECT 0.000 127.880 0.600 128.480 ;
    END
  END s_axi_wdata_2
  PIN s_axi_wdata_20
    DIRECTION INPUT ;
    USE SIGNAL ;
    ANTENNAGATEAREA 0.647700 ;
    ANTENNADIFFAREA 0.434700 ;
    PORT
      LAYER met3 ;
        RECT 0.000 54.440 0.600 55.040 ;
    END
  END s_axi_wdata_20
  PIN s_axi_wdata_21
    DIRECTION INPUT ;
    USE SIGNAL ;
    ANTENNAGATEAREA 0.647700 ;
    ANTENNADIFFAREA 0.434700 ;
    PORT
      LAYER met3 ;
        RECT 0.000 130.600 0.600 131.200 ;
    END
  END s_axi_wdata_21
  PIN s_axi_wdata_22
    DIRECTION INPUT ;
    USE SIGNAL ;
    ANTENNAGATEAREA 0.647700 ;
    ANTENNADIFFAREA 0.434700 ;
    PORT
      LAYER met3 ;
        RECT 0.000 80.280 0.600 80.880 ;
    END
  END s_axi_wdata_22
  PIN s_axi_wdata_23
    DIRECTION INPUT ;
    USE SIGNAL ;
    ANTENNAGATEAREA 0.647700 ;
    ANTENNADIFFAREA 0.434700 ;
    PORT
      LAYER met3 ;
        RECT 0.000 121.080 0.600 121.680 ;
    END
  END s_axi_wdata_23
  PIN s_axi_wdata_24
    DIRECTION INPUT ;
    USE SIGNAL ;
    ANTENNAGATEAREA 0.647700 ;
    ANTENNADIFFAREA 0.434700 ;
    PORT
      LAYER met2 ;
        RECT 84.730 0.000 85.010 0.280 ;
    END
  END s_axi_wdata_24
  PIN s_axi_wdata_25
    DIRECTION INPUT ;
    USE SIGNAL ;
    ANTENNAGATEAREA 0.647700 ;
    ANTENNADIFFAREA 0.434700 ;
    PORT
      LAYER met2 ;
        RECT 81.050 0.000 81.330 0.280 ;
    END
  END s_axi_wdata_25
  PIN s_axi_wdata_26
    DIRECTION INPUT ;
    USE SIGNAL ;
    ANTENNAGATEAREA 0.647700 ;
    ANTENNADIFFAREA 0.434700 ;
    PORT
      LAYER met3 ;
        RECT 0.000 137.400 0.600 138.000 ;
    END
  END s_axi_wdata_26
  PIN s_axi_wdata_27
    DIRECTION INPUT ;
    USE SIGNAL ;
    ANTENNAGATEAREA 0.647700 ;
    ANTENNADIFFAREA 0.434700 ;
    PORT
      LAYER met3 ;
        RECT 0.000 89.800 0.600 90.400 ;
    END
  END s_axi_wdata_27
  PIN s_axi_wdata_28
    DIRECTION INPUT ;
    USE SIGNAL ;
    ANTENNAGATEAREA 0.647700 ;
    ANTENNADIFFAREA 0.434700 ;
    PORT
      LAYER met3 ;
        RECT 0.000 129.240 0.600 129.840 ;
    END
  END s_axi_wdata_28
  PIN s_axi_wdata_29
    DIRECTION INPUT ;
    USE SIGNAL ;
    ANTENNAGATEAREA 0.647700 ;
    ANTENNADIFFAREA 0.434700 ;
    PORT
      LAYER met3 ;
        RECT 0.000 140.120 0.600 140.720 ;
    END
  END s_axi_wdata_29
  PIN s_axi_wdata_3
    DIRECTION INPUT ;
    USE SIGNAL ;
    ANTENNAGATEAREA 0.647700 ;
    ANTENNADIFFAREA 0.434700 ;
    PORT
      LAYER met3 ;
        RECT 0.000 133.320 0.600 133.920 ;
    END
  END s_axi_wdata_3
  PIN s_axi_wdata_30
    DIRECTION INPUT ;
    USE SIGNAL ;
    ANTENNAGATEAREA 0.647700 ;
    ANTENNADIFFAREA 0.434700 ;
    PORT
      LAYER met3 ;
        RECT 0.000 43.560 0.600 44.160 ;
    END
  END s_axi_wdata_30
  PIN s_axi_wdata_31
    DIRECTION INPUT ;
    USE SIGNAL ;
    ANTENNAGATEAREA 0.647700 ;
    ANTENNADIFFAREA 0.434700 ;
    PORT
      LAYER met3 ;
        RECT 0.000 126.520 0.600 127.120 ;
    END
  END s_axi_wdata_31
  PIN s_axi_wdata_4
    DIRECTION INPUT ;
    USE SIGNAL ;
    ANTENNAGATEAREA 0.647700 ;
    ANTENNADIFFAREA 0.434700 ;
    PORT
      LAYER met3 ;
        RECT 0.000 62.600 0.600 63.200 ;
    END
  END s_axi_wdata_4
  PIN s_axi_wdata_5
    DIRECTION INPUT ;
    USE SIGNAL ;
    ANTENNAGATEAREA 0.647700 ;
    ANTENNADIFFAREA 0.434700 ;
    PORT
      LAYER met3 ;
        RECT 0.000 136.040 0.600 136.640 ;
    END
  END s_axi_wdata_5
  PIN s_axi_wdata_6
    DIRECTION INPUT ;
    USE SIGNAL ;
    ANTENNAGATEAREA 0.647700 ;
    ANTENNADIFFAREA 0.434700 ;
    PORT
      LAYER met3 ;
        RECT 0.000 122.440 0.600 123.040 ;
    END
  END s_axi_wdata_6
  PIN s_axi_wdata_7
    DIRECTION INPUT ;
    USE SIGNAL ;
    ANTENNAGATEAREA 0.647700 ;
    ANTENNADIFFAREA 0.434700 ;
    PORT
      LAYER met3 ;
        RECT 0.000 134.680 0.600 135.280 ;
    END
  END s_axi_wdata_7
  PIN s_axi_wdata_8
    DIRECTION INPUT ;
    USE SIGNAL ;
    ANTENNAGATEAREA 0.647700 ;
    ANTENNADIFFAREA 0.434700 ;
    PORT
      LAYER met2 ;
        RECT 87.490 0.000 87.770 0.280 ;
    END
  END s_axi_wdata_8
  PIN s_axi_wdata_9
    DIRECTION INPUT ;
    USE SIGNAL ;
    ANTENNAGATEAREA 0.647700 ;
    ANTENNADIFFAREA 0.434700 ;
    PORT
      LAYER met2 ;
        RECT 81.970 0.000 82.250 0.280 ;
    END
  END s_axi_wdata_9
  PIN s_axi_wready
    DIRECTION OUTPUT ;
    USE SIGNAL ;
    ANTENNAGATEAREA 0.434700 ;
    ANTENNADIFFAREA 1.137600 ;
    PORT
      LAYER met3 ;
        RECT 0.000 125.160 0.600 125.760 ;
    END
  END s_axi_wready
  PIN s_axi_wstrb_0
    DIRECTION INPUT ;
    USE SIGNAL ;
    ANTENNAGATEAREA 0.647700 ;
    ANTENNADIFFAREA 0.434700 ;
    PORT
      LAYER met3 ;
        RECT 0.000 97.960 0.600 98.560 ;
    END
  END s_axi_wstrb_0
  PIN s_axi_wstrb_1
    DIRECTION INPUT ;
    USE SIGNAL ;
    ANTENNAGATEAREA 0.647700 ;
    ANTENNADIFFAREA 0.434700 ;
    PORT
      LAYER met2 ;
        RECT 85.650 0.000 85.930 0.280 ;
    END
  END s_axi_wstrb_1
  PIN s_axi_wstrb_2
    DIRECTION INPUT ;
    USE SIGNAL ;
    ANTENNAGATEAREA 0.647700 ;
    ANTENNADIFFAREA 0.434700 ;
    PORT
      LAYER met2 ;
        RECT 82.890 0.000 83.170 0.280 ;
    END
  END s_axi_wstrb_2
  PIN s_axi_wstrb_3
    DIRECTION INPUT ;
    USE SIGNAL ;
    ANTENNAGATEAREA 0.647700 ;
    ANTENNADIFFAREA 0.434700 ;
    PORT
      LAYER met2 ;
        RECT 86.570 0.000 86.850 0.280 ;
    END
  END s_axi_wstrb_3
  PIN s_axi_wvalid
    DIRECTION INPUT ;
    USE SIGNAL ;
    ANTENNAGATEAREA 0.647700 ;
    ANTENNADIFFAREA 0.434700 ;
    PORT
      LAYER met3 ;
        RECT 0.000 123.800 0.600 124.400 ;
    END
  END s_axi_wvalid
  OBS
      LAYER nwell ;
        RECT 5.330 10.795 197.070 201.365 ;
      LAYER li1 ;
        RECT 5.520 10.795 196.880 201.365 ;
      LAYER met1 ;
        RECT 5.520 6.160 196.880 204.300 ;
      LAYER met2 ;
        RECT 6.070 212.675 73.410 213.165 ;
        RECT 74.250 212.675 74.330 213.165 ;
        RECT 75.170 212.675 75.250 213.165 ;
        RECT 76.090 212.675 76.170 213.165 ;
        RECT 77.010 212.675 78.010 213.165 ;
        RECT 78.850 212.675 78.930 213.165 ;
        RECT 79.770 212.675 80.770 213.165 ;
        RECT 81.610 212.675 83.530 213.165 ;
        RECT 84.370 212.675 84.450 213.165 ;
        RECT 85.290 212.675 85.370 213.165 ;
        RECT 86.210 212.675 86.290 213.165 ;
        RECT 87.130 212.675 88.130 213.165 ;
        RECT 88.970 212.675 89.050 213.165 ;
        RECT 89.890 212.675 89.970 213.165 ;
        RECT 90.810 212.675 90.890 213.165 ;
        RECT 91.730 212.675 91.810 213.165 ;
        RECT 92.650 212.675 92.730 213.165 ;
        RECT 93.570 212.675 93.650 213.165 ;
        RECT 94.490 212.675 94.570 213.165 ;
        RECT 95.410 212.675 95.490 213.165 ;
        RECT 96.330 212.675 98.250 213.165 ;
        RECT 99.090 212.675 99.170 213.165 ;
        RECT 100.010 212.675 101.930 213.165 ;
        RECT 102.770 212.675 102.850 213.165 ;
        RECT 103.690 212.675 103.770 213.165 ;
        RECT 104.610 212.675 104.690 213.165 ;
        RECT 105.530 212.675 105.610 213.165 ;
        RECT 106.450 212.675 106.530 213.165 ;
        RECT 107.370 212.675 107.450 213.165 ;
        RECT 108.290 212.675 108.370 213.165 ;
        RECT 109.210 212.675 109.290 213.165 ;
        RECT 110.130 212.675 110.210 213.165 ;
        RECT 111.050 212.675 112.050 213.165 ;
        RECT 112.890 212.675 112.970 213.165 ;
        RECT 113.810 212.675 113.890 213.165 ;
        RECT 114.730 212.675 114.810 213.165 ;
        RECT 115.650 212.675 115.730 213.165 ;
        RECT 116.570 212.675 116.650 213.165 ;
        RECT 117.490 212.675 117.570 213.165 ;
        RECT 118.410 212.675 118.490 213.165 ;
        RECT 119.330 212.675 119.410 213.165 ;
        RECT 120.250 212.675 123.090 213.165 ;
        RECT 123.930 212.675 130.450 213.165 ;
        RECT 131.290 212.675 131.370 213.165 ;
        RECT 132.210 212.675 139.650 213.165 ;
        RECT 140.490 212.675 141.490 213.165 ;
        RECT 142.330 212.675 142.410 213.165 ;
        RECT 143.250 212.675 148.850 213.165 ;
        RECT 149.690 212.675 153.450 213.165 ;
        RECT 154.290 212.675 162.650 213.165 ;
        RECT 163.490 212.675 167.250 213.165 ;
        RECT 168.090 212.675 179.210 213.165 ;
        RECT 180.050 212.675 196.790 213.165 ;
        RECT 6.070 0.560 196.790 212.675 ;
        RECT 6.070 0.070 15.450 0.560 ;
        RECT 16.290 0.070 25.570 0.560 ;
        RECT 26.410 0.070 33.850 0.560 ;
        RECT 34.690 0.070 35.690 0.560 ;
        RECT 36.530 0.070 45.810 0.560 ;
        RECT 46.650 0.070 46.730 0.560 ;
        RECT 47.570 0.070 55.010 0.560 ;
        RECT 55.850 0.070 55.930 0.560 ;
        RECT 56.770 0.070 66.970 0.560 ;
        RECT 67.810 0.070 67.890 0.560 ;
        RECT 68.730 0.070 68.810 0.560 ;
        RECT 69.650 0.070 69.730 0.560 ;
        RECT 70.570 0.070 79.850 0.560 ;
        RECT 80.690 0.070 80.770 0.560 ;
        RECT 81.610 0.070 81.690 0.560 ;
        RECT 82.530 0.070 82.610 0.560 ;
        RECT 83.450 0.070 83.530 0.560 ;
        RECT 84.370 0.070 84.450 0.560 ;
        RECT 85.290 0.070 85.370 0.560 ;
        RECT 86.210 0.070 86.290 0.560 ;
        RECT 87.130 0.070 87.210 0.560 ;
        RECT 88.050 0.070 107.450 0.560 ;
        RECT 108.290 0.070 108.370 0.560 ;
        RECT 109.210 0.070 109.290 0.560 ;
        RECT 110.130 0.070 110.210 0.560 ;
        RECT 111.050 0.070 111.130 0.560 ;
        RECT 111.970 0.070 124.010 0.560 ;
        RECT 124.850 0.070 124.930 0.560 ;
        RECT 125.770 0.070 125.850 0.560 ;
        RECT 126.690 0.070 127.690 0.560 ;
        RECT 128.530 0.070 132.290 0.560 ;
        RECT 133.130 0.070 137.810 0.560 ;
        RECT 138.650 0.070 185.650 0.560 ;
        RECT 186.490 0.070 186.570 0.560 ;
        RECT 187.410 0.070 187.490 0.560 ;
        RECT 188.330 0.070 188.410 0.560 ;
        RECT 189.250 0.070 189.330 0.560 ;
        RECT 190.170 0.070 190.250 0.560 ;
        RECT 191.090 0.070 191.170 0.560 ;
        RECT 192.010 0.070 196.790 0.560 ;
      LAYER met3 ;
        RECT 0.600 196.880 201.915 201.445 ;
        RECT 1.000 195.480 201.915 196.880 ;
        RECT 0.600 184.640 201.915 195.480 ;
        RECT 0.600 183.240 201.515 184.640 ;
        RECT 0.600 175.120 201.915 183.240 ;
        RECT 0.600 173.720 201.515 175.120 ;
        RECT 0.600 160.160 201.915 173.720 ;
        RECT 0.600 158.760 201.515 160.160 ;
        RECT 0.600 156.080 201.915 158.760 ;
        RECT 0.600 153.320 201.515 156.080 ;
        RECT 0.600 147.920 201.915 153.320 ;
        RECT 0.600 146.520 201.515 147.920 ;
        RECT 0.600 143.840 201.915 146.520 ;
        RECT 0.600 141.120 201.515 143.840 ;
        RECT 1.000 141.080 201.515 141.120 ;
        RECT 1.000 135.680 201.915 141.080 ;
        RECT 1.000 134.280 201.515 135.680 ;
        RECT 1.000 132.960 201.915 134.280 ;
        RECT 1.000 131.560 201.515 132.960 ;
        RECT 1.000 130.240 201.915 131.560 ;
        RECT 1.000 128.840 201.515 130.240 ;
        RECT 1.000 124.800 201.915 128.840 ;
        RECT 1.000 117.960 201.515 124.800 ;
        RECT 1.000 108.480 201.915 117.960 ;
        RECT 1.000 104.360 201.515 108.480 ;
        RECT 0.600 103.040 201.915 104.360 ;
        RECT 1.000 100.280 201.515 103.040 ;
        RECT 1.000 98.960 201.915 100.280 ;
        RECT 1.000 97.560 201.515 98.960 ;
        RECT 1.000 96.240 201.915 97.560 ;
        RECT 1.000 94.840 201.515 96.240 ;
        RECT 0.600 93.520 201.915 94.840 ;
        RECT 0.600 92.160 201.515 93.520 ;
        RECT 1.000 89.400 201.515 92.160 ;
        RECT 1.000 85.320 201.915 89.400 ;
        RECT 0.600 84.000 201.915 85.320 ;
        RECT 0.600 81.280 201.515 84.000 ;
        RECT 1.000 79.880 201.515 81.280 ;
        RECT 0.600 78.560 201.515 79.880 ;
        RECT 1.000 78.520 201.515 78.560 ;
        RECT 1.000 74.440 201.915 78.520 ;
        RECT 0.600 73.120 201.915 74.440 ;
        RECT 0.600 71.760 201.515 73.120 ;
        RECT 1.000 71.720 201.515 71.760 ;
        RECT 1.000 70.400 201.915 71.720 ;
        RECT 1.000 70.360 201.515 70.400 ;
        RECT 0.600 67.640 201.515 70.360 ;
        RECT 0.600 66.320 201.915 67.640 ;
        RECT 1.000 64.920 201.915 66.320 ;
        RECT 0.600 63.600 201.915 64.920 ;
        RECT 1.000 62.240 201.915 63.600 ;
        RECT 1.000 60.840 201.515 62.240 ;
        RECT 1.000 59.520 201.915 60.840 ;
        RECT 1.000 59.480 201.515 59.520 ;
        RECT 0.600 58.120 201.515 59.480 ;
        RECT 0.600 55.440 201.915 58.120 ;
        RECT 1.000 54.040 201.915 55.440 ;
        RECT 0.600 51.360 201.915 54.040 ;
        RECT 1.000 48.600 201.915 51.360 ;
        RECT 0.600 44.560 201.915 48.600 ;
        RECT 1.000 41.800 201.915 44.560 ;
        RECT 0.600 29.600 201.915 41.800 ;
        RECT 1.000 28.200 201.915 29.600 ;
        RECT 0.600 16.000 201.915 28.200 ;
        RECT 0.600 14.600 201.515 16.000 ;
        RECT 0.600 10.715 201.915 14.600 ;
      LAYER met4 ;
        RECT 10.415 115.095 20.640 200.425 ;
        RECT 23.040 115.095 23.940 200.425 ;
        RECT 26.340 115.095 117.465 200.425 ;
  END
END plic
END LIBRARY

